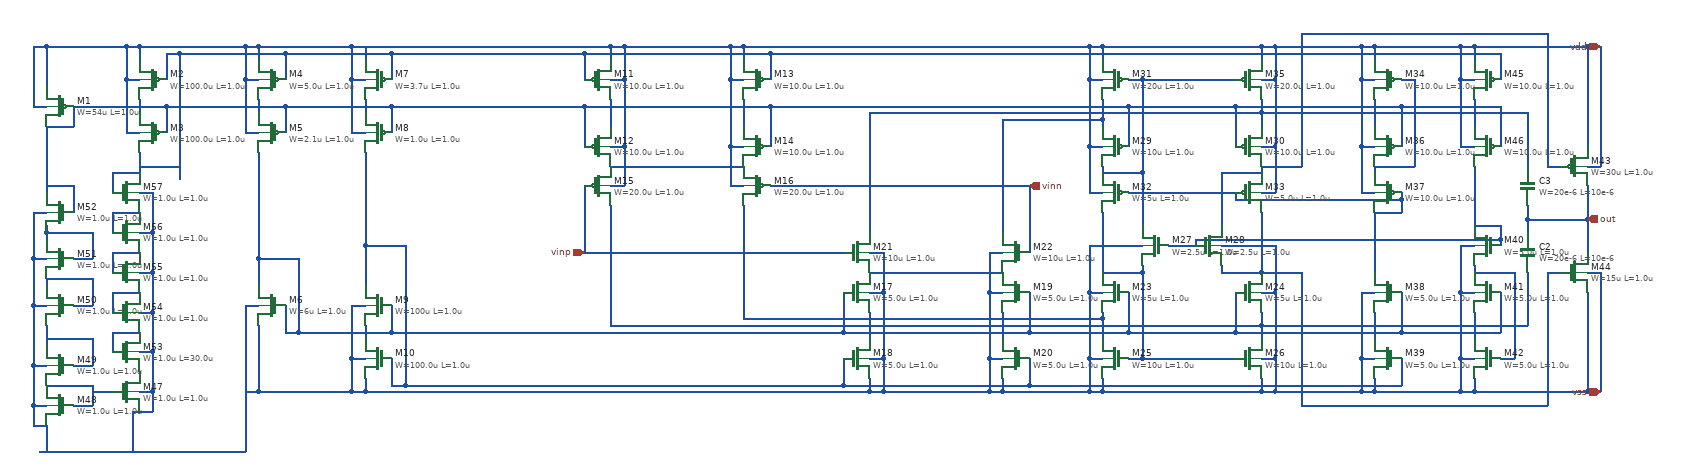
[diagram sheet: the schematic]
v {xschem version=3.4.8RC file_version=1.3}
G {}
K {}
V {}
S {}
F {}
E {}
N -450 -60 -430 -60 {
lab=vdd}
N -270 -60 -250 -60 {
lab=vdd}
N -450 -270 -450 -250 {
lab=vdd}
N -450 -220 -430 -220 {
lab=vdd}
N -490 -260 -490 -220 {
lab=#net1}
N 270 200 270 250 {
lab=vss}
N 270 200 290 200 {
lab=vss}
N 290 230 290 250 {
lab=vss}
N 290 -270 290 -250 {
lab=vdd}
N 270 -220 290 -220 {
lab=vdd}
N 530 -270 530 -250 {
lab=vdd}
N 530 -220 550 -220 {
lab=vdd}
N 550 -220 550 -120 {
lab=vdd}
N 530 200 550 200 {
lab=vss}
N 530 230 530 250 {
lab=vss}
N -490 -60 -490 40 {
lab=vinp}
N 120 40 140 40 {
lab=vss}
N -60 100 -40 100 {
lab=vss}
N -40 200 -40 250 {
lab=vss}
N -60 200 -40 200 {
lab=vss}
N -60 130 -60 170 {
lab=#net2}
N -60 230 -60 250 {
lab=vss}
N -100 200 -100 240 {
lab=#net3}
N -100 100 -100 160 {
lab=#net4}
N -450 -120 -430 -120 {
lab=vdd}
N -450 -190 -450 -150 {
lab=#net5}
N -490 -180 -490 -120 {
lab=#net6}
N 270 -220 270 -120 {
lab=vdd}
N 270 -120 290 -120 {
lab=vdd}
N 290 -160 290 -150 {
lab=#net7}
N 270 100 290 100 {
lab=vss}
N 270 100 270 200 {
lab=vss}
N 290 140 290 170 {
lab=#net8}
N 530 150 530 170 {
lab=#net9}
N 530 100 550 100 {
lab=vss}
N -210 -60 180 -60 {
lab=vinn}
N 180 -60 180 40 {
lab=vinn}
N 530 -120 550 -120 {
lab=vdd}
N 530 -170 530 -150 {
lab=#net10}
N -450 -90 -250 -90 {
lab=#net11}
N -490 40 -100 40 {
lab=vinp}
N -60 70 140 70 {
lab=#net12}
N 290 -90 290 -80 {
lab=#net13}
N 270 -50 290 -50 {
lab=vdd}
N 270 -120 270 -50 {
lab=vdd}
N 350 200 490 200 {
lab=#net14}
N 550 200 550 250 {
lab=vss}
N 390 30 430 30 {
lab=#net15}
N 530 -50 550 -50 {
lab=vdd}
N 550 -120 550 -50 {
lab=vdd}
N 530 -90 530 -80 {
lab=#net16}
N 470 30 550 30 {
lab=vss}
N 550 30 550 100 {
lab=vss}
N 1020 -10 1020 40 {
lab=out}
N 1020 -90 1040 -90 {
lab=vdd}
N 1040 -270 1040 -90 {
lab=vdd}
N 700 -270 830 -270 {
lab=vdd}
N 1020 70 1040 70 {
lab=vss}
N 1040 70 1040 250 {
lab=vss}
N 1020 100 1020 250 {
lab=vss}
N 1020 -270 1020 -120 {
lab=vdd}
N 680 -220 700 -220 {
lab=vdd}
N 680 -270 680 -220 {
lab=vdd}
N 700 -270 700 -250 {
lab=vdd}
N 700 -190 700 -150 {
lab=#net17}
N 680 -120 700 -120 {
lab=vdd}
N 680 -220 680 -120 {
lab=vdd}
N 700 -90 700 -80 {
lab=#net18}
N 680 -50 700 -50 {
lab=vdd}
N 680 -120 680 -50 {
lab=vdd}
N 680 100 700 100 {
lab=vss}
N 680 200 680 250 {
lab=vss}
N 680 200 700 200 {
lab=vss}
N 700 130 700 170 {
lab=#net19}
N 700 230 700 250 {
lab=vss}
N 740 200 740 240 {
lab=#net3}
N 740 100 740 160 {
lab=#net4}
N 830 -220 850 -220 {
lab=vdd}
N 830 -270 830 -220 {
lab=vdd}
N 850 -270 850 -250 {
lab=vdd}
N 850 -190 850 -150 {
lab=#net20}
N 830 -120 850 -120 {
lab=vdd}
N 830 -220 830 -120 {
lab=vdd}
N 830 100 850 100 {
lab=vss}
N 830 200 830 250 {
lab=vss}
N 830 200 850 200 {
lab=vss}
N 850 130 850 170 {
lab=#net21}
N 850 230 850 250 {
lab=vss}
N 850 60 850 70 {
lab=#net22}
N 830 30 850 30 {
lab=vss}
N 830 30 830 100 {
lab=vss}
N 850 -270 1020 -270 {
lab=vdd}
N -250 -270 -250 -250 {
lab=vdd}
N -270 -220 -250 -220 {
lab=vdd}
N -210 -260 -210 -220 {
lab=#net1}
N -270 -120 -250 -120 {
lab=vdd}
N -250 -190 -250 -150 {
lab=#net23}
N -210 -180 -210 -120 {
lab=#net6}
N 120 100 140 100 {
lab=vss}
N 120 200 140 200 {
lab=vss}
N 140 130 140 170 {
lab=#net24}
N 140 230 140 250 {
lab=vss}
N 180 200 180 240 {
lab=#net3}
N 180 100 180 160 {
lab=#net4}
N -60 40 -40 40 {
lab=vss}
N 740 -180 740 -120 {
lab=#net6}
N 740 -220 760 -220 {
lab=#net18}
N 760 -220 760 -90 {
lab=#net18}
N 700 -90 760 -90 {
lab=#net18}
N 740 -40 740 -20 {
lab=#net25}
N 700 -20 740 -20 {
lab=#net25}
N 700 -20 700 70 {
lab=#net25}
N 890 -260 890 -220 {
lab=#net1}
N 890 -180 890 -120 {
lab=#net6}
N 490 160 740 160 {
lab=#net4}
N 890 100 890 160 {
lab=#net4}
N 890 200 910 200 {
lab=#net22}
N 910 70 910 200 {
lab=#net22}
N 850 70 910 70 {
lab=#net22}
N 890 20 890 30 {
lab=#net15}
N 850 0 890 0 {
lab=#net15}
N 850 -90 850 0 {
lab=#net15}
N 350 -220 490 -220 {
lab=#net13}
N 330 -180 330 -120 {
lab=#net6}
N 490 -180 490 -120 {
lab=#net6}
N 330 -50 490 -50 {
lab=#net25}
N 290 -20 290 70 {
lab=#net14}
N 350 60 350 70 {
lab=#net14}
N 290 70 350 70 {
lab=#net14}
N 470 60 470 70 {
lab=#net26}
N 470 70 530 70 {
lab=#net26}
N 270 30 350 30 {
lab=vss}
N 270 30 270 100 {
lab=vss}
N 530 -20 530 70 {
lab=#net26}
N 350 -80 350 0 {
lab=#net13}
N 290 -80 350 -80 {
lab=#net13}
N 470 -80 470 0 {
lab=#net16}
N 470 -80 530 -80 {
lab=#net16}
N 740 -180 890 -180 {
lab=#net6}
N 180 240 740 240 {
lab=#net3}
N 740 160 890 160 {
lab=#net4}
N 490 -40 740 -40 {
lab=#net25}
N 490 -50 490 -40 {
lab=#net25}
N 430 20 890 20 {
lab=#net15}
N 430 20 430 30 {
lab=#net15}
N -450 -30 -450 150 {
lab=#net9}
N -250 -30 -250 140 {
lab=#net8}
N -60 -170 -60 10 {
lab=#net10}
N 140 -160 140 10 {
lab=#net7}
N 330 100 330 160 {
lab=#net4}
N 490 100 490 160 {
lab=#net4}
N 350 70 350 200 {
lab=#net14}
N 350 -220 350 -80 {
lab=#net13}
N 1020 -270 1040 -270 {
lab=vdd}
N 960 -90 980 -90 {
lab=#net16}
N 960 -290 960 -90 {
lab=#net16}
N 590 -290 960 -290 {
lab=#net16}
N 590 -290 590 -90 {
lab=#net16}
N 530 -90 590 -90 {
lab=#net16}
N 960 70 980 70 {
lab=#net26}
N 960 70 960 270 {
lab=#net26}
N 590 270 960 270 {
lab=#net26}
N 590 70 590 270 {
lab=#net26}
N 530 70 590 70 {
lab=#net26}
N 530 150 930 150 {
lab=#net9}
N 930 -10 930 10 {
lab=out}
N -60 -170 530 -170 {
lab=#net10}
N 140 -160 290 -160 {
lab=#net7}
N -250 140 290 140 {
lab=#net8}
N -450 150 530 150 {
lab=#net9}
N 270 -270 290 -270 {
lab=vdd}
N 530 -270 550 -270 {
lab=vdd}
N 1020 250 1040 250 {
lab=vss}
N -100 160 180 160 {
lab=#net4}
N -100 240 180 240 {
lab=#net3}
N -490 -260 -210 -260 {
lab=#net1}
N -490 -180 -210 -180 {
lab=#net6}
N 490 -180 740 -180 {
lab=#net6}
N -210 -260 890 -260 {
lab=#net1}
N -270 -270 -250 -270 {
lab=vdd}
N -640 -260 -490 -260 {
lab=#net1}
N -640 -180 -490 -180 {
lab=#net6}
N -640 160 -100 160 {
lab=#net4}
N -620 240 -100 240 {
lab=#net3}
N 930 -10 1020 -10 {
lab=out}
N 930 70 930 150 {
lab=#net9}
N 530 -170 930 -170 {
lab=#net10}
N 930 -170 930 -90 {
lab=#net10}
N 930 -30 930 -10 {
lab=out}
N -270 -220 -270 -120 {
lab=vdd}
N -430 -220 -430 -120 {
lab=vdd}
N 120 200 120 250 {
lab=vss}
N -40 40 -40 100 {
lab=vss}
N 120 40 120 100 {
lab=vss}
N -430 -120 -430 -60 {
lab=vdd}
N -270 -120 -270 -60 {
lab=vdd}
N -430 -270 -430 -220 {
lab=vdd}
N 140 250 270 250 {
lab=vss}
N 270 250 290 250 {
lab=vss}
N 270 -270 270 -220 {
lab=vdd}
N 290 -270 530 -270 {
lab=vdd}
N 550 -270 550 -220 {
lab=vdd}
N 550 100 550 200 {
lab=vss}
N 290 250 530 250 {
lab=vss}
N -60 250 -40 250 {
lab=vss}
N -40 100 -40 200 {
lab=vss}
N 530 250 550 250 {
lab=vss}
N 850 250 1020 250 {
lab=vss}
N 550 -270 680 -270 {
lab=vdd}
N 680 -270 700 -270 {
lab=vdd}
N 550 250 680 250 {
lab=vss}
N 680 100 680 200 {
lab=vss}
N 680 250 700 250 {
lab=vss}
N 830 -270 850 -270 {
lab=vdd}
N 700 250 830 250 {
lab=vss}
N 830 100 830 200 {
lab=vss}
N 830 250 850 250 {
lab=vss}
N -270 -270 -270 -220 {
lab=vdd}
N 120 100 120 200 {
lab=vss}
N 120 250 140 250 {
lab=vss}
N -210 -180 330 -180 {
lab=#net6}
N 330 -180 490 -180 {
lab=#net6}
N 740 -50 740 -40 {
lab=#net25}
N 890 0 890 20 {
lab=#net15}
N 180 160 330 160 {
lab=#net4}
N 330 160 490 160 {
lab=#net4}
N 330 200 350 200 {
lab=#net14}
N 330 -220 350 -220 {
lab=#net13}
N 530 130 530 150 {
lab=#net9}
N 530 -190 530 -170 {
lab=#net10}
N 290 -190 290 -160 {
lab=#net7}
N 290 130 290 140 {
lab=#net8}
N 1020 -60 1020 -10 {
lab=out}
N -40 250 120 250 {
lab=vss}
N -450 -270 -430 -270 {
lab=vdd}
N -250 -270 270 -270 {
lab=vdd}
N -430 -270 -270 -270 {
lab=vdd}
N -740 -260 -590 -260 {
lab=#net1}
N -740 -180 -590 -180 {
lab=#net6}
N -740 160 -600 160 {lab=#net4}
N -720 240 -600 240 {lab=#net3}
N -800 250 -60 250 {lab=vss}
N -780 -270 -450 -270 {lab=vdd}
N -840 120 -820 120 {
lab=vss}
N -840 200 -840 250 {
lab=vss}
N -840 200 -820 200 {
lab=vss}
N -820 150 -820 170 {
lab=#net27}
N -820 230 -820 250 {
lab=vss}
N -820 -270 -820 -250 {
lab=vdd}
N -840 -220 -820 -220 {
lab=vdd}
N -840 -140 -820 -140 {
lab=vdd}
N -840 -220 -840 -140 {
lab=vdd}
N -820 -190 -820 -170 {
lab=#net28}
N -780 -180 -780 -140 {
lab=#net6}
N -780 -260 -780 -220 {
lab=#net1}
N -980 -270 -980 -250 {
lab=vdd}
N -1000 -220 -980 -220 {
lab=vdd}
N -1000 -140 -980 -140 {
lab=vdd}
N -1000 -220 -1000 -140 {
lab=vdd}
N -980 -190 -980 -170 {
lab=#net29}
N -940 -180 -940 -140 {
lab=#net6}
N -940 -260 -940 -220 {
lab=#net1}
N -1000 120 -980 120 {
lab=vss}
N -1000 120 -1000 250 {
lab=vss}
N -980 150 -980 250 {
lab=vss}
N -940 120 -940 160 {
lab=#net4}
N -940 160 -920 160 {
lab=#net4}
N -980 50 -920 50 {
lab=#net4}
N -780 120 -780 160 {
lab=#net4}
N -780 200 -780 240 {
lab=#net3}
N -780 240 -760 240 {
lab=#net3}
N -920 160 -780 160 {
lab=#net4}
N -820 30 -760 30 {
lab=#net3}
N -980 -110 -980 50 {
lab=#net4}
N -820 -110 -820 30 {
lab=#net3}
N -920 50 -920 160 {
lab=#net4}
N -760 30 -760 240 {
lab=#net3}
N -820 30 -820 90 {
lab=#net3}
N -980 50 -980 90 {
lab=#net4}
N -780 -260 -630 -260 {
lab=#net1}
N -780 -180 -630 -180 {
lab=#net6}
N -1170 340 -1010 340 {
lab=vss}
N -1160 -270 -1160 -250 {
lab=vdd}
N -1180 -220 -1160 -220 {
lab=vdd}
N -1180 -140 -1160 -140 {
lab=vdd}
N -1180 -220 -1180 -140 {
lab=vdd}
N -1160 -190 -1160 -170 {
lab=#net30}
N -1120 -180 -1120 -140 {
lab=#net6}
N -1120 -260 -1120 -220 {
lab=#net1}
N -1300 -270 -1300 -190 {
lab=vdd}
N -1320 -270 -1320 -180 {
lab=vdd}
N -1240 -180 -1120 -180 {
lab=#net6}
N -1300 -70 -1300 -50 {
lab=#net6}
N -1160 -110 -1160 -70 {
lab=#net1}
N -1100 -260 -1100 -70 {
lab=#net1}
N -1230 250 -1200 250 {
lab=#net31}
N -1320 270 -1300 270 {
lab=vss}
N -1320 270 -1320 300 {
lab=vss}
N -1320 300 -1300 300 {
lab=vss}
N -1160 250 -1140 250 {
lab=vss}
N -1140 250 -1140 280 {
lab=vss}
N -1160 280 -1140 280 {
lab=vss}
N -1320 210 -1300 210 {
lab=vss}
N -1320 210 -1320 270 {
lab=vss}
N -1230 190 -1230 210 {
lab=#net32}
N -980 250 -840 250 {
lab=vss}
N -840 120 -840 200 {
lab=vss}
N -840 250 -820 250 {
lab=vss}
N -840 -270 -820 -270 {
lab=vdd}
N -840 -270 -840 -220 {
lab=vdd}
N -940 -180 -780 -180 {
lab=#net6}
N -940 -260 -780 -260 {
lab=#net1}
N -1000 -270 -980 -270 {
lab=vdd}
N -1000 -270 -1000 -220 {
lab=vdd}
N -1120 -180 -940 -180 {
lab=#net6}
N -1100 -260 -940 -260 {
lab=#net1}
N -1000 250 -980 250 {
lab=vss}
N -1180 -270 -1160 -270 {
lab=vdd}
N -1180 -270 -1180 -220 {
lab=vdd}
N -1320 -270 -1300 -270 {
lab=vdd}
N -1260 -180 -1240 -180 {
lab=#net6}
N -1120 -260 -1100 -260 {
lab=#net1}
N -1300 340 -1160 340 {
lab=vss}
N -1260 210 -1230 210 {
lab=#net32}
N -1260 270 -1230 270 {
lab=#net31}
N -980 -270 -840 -270 {
lab=vdd}
N -1160 -270 -1000 -270 {
lab=vdd}
N -1300 -270 -1180 -270 {
lab=vdd}
N -780 160 -640 160 {lab=#net4}
N -760 240 -640 240 {lab=#net3}
N -1300 150 -1300 180 {lab=#net32}
N -1260 120 -1230 120 {lab=#net33}
N -1320 120 -1300 120 {lab=vss}
N -1320 120 -1320 210 {lab=vss}
N -1230 80 -1230 120 {lab=#net33}
N -1300 80 -1230 80 {lab=#net33}
N -1230 170 -1230 190 {lab=#net32}
N -1300 170 -1230 170 {lab=#net32}
N -1000 240 -1000 340 {lab=vss}
N -1030 340 -1000 340 {lab=vss}
N -1170 280 -1170 340 {lab=vss}
N -1170 280 -1160 280 {lab=vss}
N -1260 50 -1230 50 {lab=#net34}
N -1230 10 -1230 50 {lab=#net34}
N -1310 340 -1280 340 {lab=vss}
N -1300 80 -1300 90 {lab=#net33}
N -1300 0 -1300 10 {lab=#net34}
N -1300 10 -1280 10 {lab=#net34}
N -1300 10 -1300 20 {lab=#net34}
N -1320 50 -1320 120 {lab=vss}
N -1320 50 -1300 50 {lab=vss}
N -1300 240 -1230 240 {lab=#net31}
N -1230 240 -1230 270 {lab=#net31}
N -1320 -20 -1300 -20 {lab=vss}
N -1320 -20 -1320 50 {lab=vss}
N -1260 -60 -1260 -20 {lab=#net6}
N -1300 -60 -1260 -60 {lab=#net6}
N -1320 -180 -1300 -180 {lab=vdd}
N -1260 -180 -1260 -150 {lab=#net6}
N -1300 -150 -1260 -150 {lab=#net6}
N -1300 -150 -1300 -90 {lab=#net6}
N -1280 10 -1230 10 {lab=#net34}
N -1300 300 -1300 340 {lab=vss}
N -1300 -90 -1300 -70 {lab=#net6}
N -1200 160 -1200 190 {lab=#net35}
N -1200 160 -1160 160 {lab=#net35}
N -1160 190 -1140 190 {lab=vss}
N -1140 190 -1140 250 {lab=vss}
N -1160 190 -1140 190 {
lab=vss}
N -1200 100 -1200 130 {lab=#net36}
N -1200 100 -1160 100 {lab=#net36}
N -1160 130 -1140 130 {lab=vss}
N -1140 130 -1140 190 {lab=vss}
N -1200 40 -1200 70 {lab=#net37}
N -1200 40 -1160 40 {lab=#net37}
N -1160 70 -1140 70 {lab=vss}
N -1140 70 -1140 130 {lab=vss}
N -1200 -20 -1200 10 {lab=#net38}
N -1200 -20 -1160 -20 {lab=#net38}
N -1160 10 -1140 10 {lab=vss}
N -1140 10 -1140 70 {lab=vss}
N -1200 -80 -1200 -50 {lab=#net1}
N -1200 -80 -1160 -80 {lab=#net1}
N -1160 -50 -1140 -50 {lab=vss}
N -1140 -50 -1140 10 {lab=vss}
N -1160 -90 -1100 -90 {lab=#net1}
N -830 -270 -780 -270 {lab=vdd}
N -820 250 -790 250 {lab=vss}
C {devices/opin.sym} 1020 -10 0 0 {name=p1 lab=out}
C {devices/iopin.sym} 1040 -270 0 0 {name=p3 lab=vdd}
C {devices/iopin.sym} 1040 250 0 0 {name=p4 lab=vss}
C {devices/ipin.sym} -490 40 0 0 {name=p2 lab=vinp}
C {devices/ipin.sym} 180 -60 0 1 {name=p5 lab=vinn}
C {symbols/pfet_06v0.sym} -470 -220 0 0 {name=M11
L=1.0u
W=10.0u
nf=1
m=1
ad="'int((nf+1)/2) * W/nf * 0.18u'"
pd="'2*int((nf+1)/2) * (W/nf + 0.18u)'"
as="'int((nf+2)/2) * W/nf * 0.18u'"
ps="'2*int((nf+2)/2) * (W/nf + 0.18u)'"
nrd="'0.18u / W'" nrs="'0.18u / W'"
sa=0 sb=0 sd=0
model=pfet_06v0
spiceprefix=X
}
C {symbols/pfet_06v0.sym} -470 -120 0 0 {name=M12
L=1.0u
W=10.0u
nf=1
m=1
ad="'int((nf+1)/2) * W/nf * 0.18u'"
pd="'2*int((nf+1)/2) * (W/nf + 0.18u)'"
as="'int((nf+2)/2) * W/nf * 0.18u'"
ps="'2*int((nf+2)/2) * (W/nf + 0.18u)'"
nrd="'0.18u / W'" nrs="'0.18u / W'"
sa=0 sb=0 sd=0
model=pfet_06v0
spiceprefix=X
}
C {symbols/pfet_06v0.sym} -230 -220 0 1 {name=M13
L=1.0u
W=10.0u
nf=1
m=1
ad="'int((nf+1)/2) * W/nf * 0.18u'"
pd="'2*int((nf+1)/2) * (W/nf + 0.18u)'"
as="'int((nf+2)/2) * W/nf * 0.18u'"
ps="'2*int((nf+2)/2) * (W/nf + 0.18u)'"
nrd="'0.18u / W'" nrs="'0.18u / W'"
sa=0 sb=0 sd=0
model=pfet_06v0
spiceprefix=X
}
C {symbols/pfet_06v0.sym} -230 -120 0 1 {name=M14
L=1.0u
W=10.0u
nf=1
m=1
ad="'int((nf+1)/2) * W/nf * 0.18u'"
pd="'2*int((nf+1)/2) * (W/nf + 0.18u)'"
as="'int((nf+2)/2) * W/nf * 0.18u'"
ps="'2*int((nf+2)/2) * (W/nf + 0.18u)'"
nrd="'0.18u / W'" nrs="'0.18u / W'"
sa=0 sb=0 sd=0
model=pfet_06v0
spiceprefix=X
}
C {symbols/pfet_06v0.sym} -470 -60 0 0 {name=M15
L=1.0u
W=20.0u
nf=2
m=1
ad="'int((nf+1)/2) * W/nf * 0.18u'"
pd="'2*int((nf+1)/2) * (W/nf + 0.18u)'"
as="'int((nf+2)/2) * W/nf * 0.18u'"
ps="'2*int((nf+2)/2) * (W/nf + 0.18u)'"
nrd="'0.18u / W'" nrs="'0.18u / W'"
sa=0 sb=0 sd=0
model=pfet_06v0
spiceprefix=X
}
C {symbols/pfet_06v0.sym} -230 -60 0 1 {name=M16
L=1.0u
W=20.0u
nf=2
m=1
ad="'int((nf+1)/2) * W/nf * 0.18u'"
pd="'2*int((nf+1)/2) * (W/nf + 0.18u)'"
as="'int((nf+2)/2) * W/nf * 0.18u'"
ps="'2*int((nf+2)/2) * (W/nf + 0.18u)'"
nrd="'0.18u / W'" nrs="'0.18u / W'"
sa=0 sb=0 sd=0
model=pfet_06v0
spiceprefix=X
}
C {symbols/nfet_06v0.sym} -80 100 0 0 {name=M17
L=1.0u
W=5.0u
nf=1
m=1
ad="'int((nf+1)/2) * W/nf * 0.18u'"
pd="'2*int((nf+1)/2) * (W/nf + 0.18u)'"
as="'int((nf+2)/2) * W/nf * 0.18u'"
ps="'2*int((nf+2)/2) * (W/nf + 0.18u)'"
nrd="'0.18u / W'" nrs="'0.18u / W'"
sa=0 sb=0 sd=0
model=nfet_06v0
spiceprefix=X
}
C {symbols/nfet_06v0.sym} -80 200 0 0 {name=M18
L=1.0u
W=5.0u
nf=1
m=1
ad="'int((nf+1)/2) * W/nf * 0.18u'"
pd="'2*int((nf+1)/2) * (W/nf + 0.18u)'"
as="'int((nf+2)/2) * W/nf * 0.18u'"
ps="'2*int((nf+2)/2) * (W/nf + 0.18u)'"
nrd="'0.18u / W'" nrs="'0.18u / W'"
sa=0 sb=0 sd=0
model=nfet_06v0
spiceprefix=X
}
C {symbols/nfet_06v0.sym} 160 100 0 1 {name=M19
L=1.0u
W=5.0u
nf=1
m=1
ad="'int((nf+1)/2) * W/nf * 0.18u'"
pd="'2*int((nf+1)/2) * (W/nf + 0.18u)'"
as="'int((nf+2)/2) * W/nf * 0.18u'"
ps="'2*int((nf+2)/2) * (W/nf + 0.18u)'"
nrd="'0.18u / W'" nrs="'0.18u / W'"
sa=0 sb=0 sd=0
model=nfet_06v0
spiceprefix=X
}
C {symbols/nfet_06v0.sym} 160 200 0 1 {name=M20
L=1.0u
W=5.0u
nf=1
m=1
ad="'int((nf+1)/2) * W/nf * 0.18u'"
pd="'2*int((nf+1)/2) * (W/nf + 0.18u)'"
as="'int((nf+2)/2) * W/nf * 0.18u'"
ps="'2*int((nf+2)/2) * (W/nf + 0.18u)'"
nrd="'0.18u / W'" nrs="'0.18u / W'"
sa=0 sb=0 sd=0
model=nfet_06v0
spiceprefix=X
}
C {symbols/nfet_06v0.sym} -80 40 0 0 {name=M21
L=1.0u
W=10u
nf=2
m=1
ad="'int((nf+1)/2) * W/nf * 0.18u'"
pd="'2*int((nf+1)/2) * (W/nf + 0.18u)'"
as="'int((nf+2)/2) * W/nf * 0.18u'"
ps="'2*int((nf+2)/2) * (W/nf + 0.18u)'"
nrd="'0.18u / W'" nrs="'0.18u / W'"
sa=0 sb=0 sd=0
model=nfet_06v0
spiceprefix=X
}
C {symbols/nfet_06v0.sym} 160 40 0 1 {name=M22
L=1.0u
W=10u
nf=2
m=1
ad="'int((nf+1)/2) * W/nf * 0.18u'"
pd="'2*int((nf+1)/2) * (W/nf + 0.18u)'"
as="'int((nf+2)/2) * W/nf * 0.18u'"
ps="'2*int((nf+2)/2) * (W/nf + 0.18u)'"
nrd="'0.18u / W'" nrs="'0.18u / W'"
sa=0 sb=0 sd=0
model=nfet_06v0
spiceprefix=X
}
C {symbols/pfet_06v0.sym} 310 -120 0 1 {name=M29
L=1.0u
W=10u
nf=2
m=1
ad="'int((nf+1)/2) * W/nf * 0.18u'"
pd="'2*int((nf+1)/2) * (W/nf + 0.18u)'"
as="'int((nf+2)/2) * W/nf * 0.18u'"
ps="'2*int((nf+2)/2) * (W/nf + 0.18u)'"
nrd="'0.18u / W'" nrs="'0.18u / W'"
sa=0 sb=0 sd=0
model=pfet_06v0
spiceprefix=X
}
C {symbols/pfet_06v0.sym} 510 -120 0 0 {name=M30
L=1.0u
W=10.0u
nf=2
m=1
ad="'int((nf+1)/2) * W/nf * 0.18u'"
pd="'2*int((nf+1)/2) * (W/nf + 0.18u)'"
as="'int((nf+2)/2) * W/nf * 0.18u'"
ps="'2*int((nf+2)/2) * (W/nf + 0.18u)'"
nrd="'0.18u / W'" nrs="'0.18u / W'"
sa=0 sb=0 sd=0
model=pfet_06v0
spiceprefix=X
}
C {symbols/pfet_06v0.sym} 310 -220 0 1 {name=M31
L=1.0u
W=20u
nf=4
m=1
ad="'int((nf+1)/2) * W/nf * 0.18u'"
pd="'2*int((nf+1)/2) * (W/nf + 0.18u)'"
as="'int((nf+2)/2) * W/nf * 0.18u'"
ps="'2*int((nf+2)/2) * (W/nf + 0.18u)'"
nrd="'0.18u / W'" nrs="'0.18u / W'"
sa=0 sb=0 sd=0
model=pfet_06v0
spiceprefix=X
}
C {symbols/pfet_06v0.sym} 510 -220 0 0 {name=M35
L=1.0u
W=20.0u
nf=4
m=1
ad="'int((nf+1)/2) * W/nf * 0.18u'"
pd="'2*int((nf+1)/2) * (W/nf + 0.18u)'"
as="'int((nf+2)/2) * W/nf * 0.18u'"
ps="'2*int((nf+2)/2) * (W/nf + 0.18u)'"
nrd="'0.18u / W'" nrs="'0.18u / W'"
sa=0 sb=0 sd=0
model=pfet_06v0
spiceprefix=X
}
C {symbols/pfet_06v0.sym} 310 -50 0 1 {name=M32
L=1.0u
W=5u
nf=1
m=1
ad="'int((nf+1)/2) * W/nf * 0.18u'"
pd="'2*int((nf+1)/2) * (W/nf + 0.18u)'"
as="'int((nf+2)/2) * W/nf * 0.18u'"
ps="'2*int((nf+2)/2) * (W/nf + 0.18u)'"
nrd="'0.18u / W'" nrs="'0.18u / W'"
sa=0 sb=0 sd=0
model=pfet_06v0
spiceprefix=X
}
C {symbols/pfet_06v0.sym} 510 -50 0 0 {name=M33
L=1.0u
W=5.0u
nf=1
m=1
ad="'int((nf+1)/2) * W/nf * 0.18u'"
pd="'2*int((nf+1)/2) * (W/nf + 0.18u)'"
as="'int((nf+2)/2) * W/nf * 0.18u'"
ps="'2*int((nf+2)/2) * (W/nf + 0.18u)'"
nrd="'0.18u / W'" nrs="'0.18u / W'"
sa=0 sb=0 sd=0
model=pfet_06v0
spiceprefix=X
}
C {symbols/nfet_06v0.sym} 310 100 0 1 {name=M23
L=1.0u
W=5u
nf=2
m=1
ad="'int((nf+1)/2) * W/nf * 0.18u'"
pd="'2*int((nf+1)/2) * (W/nf + 0.18u)'"
as="'int((nf+2)/2) * W/nf * 0.18u'"
ps="'2*int((nf+2)/2) * (W/nf + 0.18u)'"
nrd="'0.18u / W'" nrs="'0.18u / W'"
sa=0 sb=0 sd=0
model=nfet_06v0
spiceprefix=X
}
C {symbols/nfet_06v0.sym} 510 100 0 0 {name=M24
L=1.0u
W=5u
nf=2
m=1
ad="'int((nf+1)/2) * W/nf * 0.18u'"
pd="'2*int((nf+1)/2) * (W/nf + 0.18u)'"
as="'int((nf+2)/2) * W/nf * 0.18u'"
ps="'2*int((nf+2)/2) * (W/nf + 0.18u)'"
nrd="'0.18u / W'" nrs="'0.18u / W'"
sa=0 sb=0 sd=0
model=nfet_06v0
spiceprefix=X
}
C {symbols/nfet_06v0.sym} 310 200 0 1 {name=M25
L=1.0u
W=10u
nf=4
m=1
ad="'int((nf+1)/2) * W/nf * 0.18u'"
pd="'2*int((nf+1)/2) * (W/nf + 0.18u)'"
as="'int((nf+2)/2) * W/nf * 0.18u'"
ps="'2*int((nf+2)/2) * (W/nf + 0.18u)'"
nrd="'0.18u / W'" nrs="'0.18u / W'"
sa=0 sb=0 sd=0
model=nfet_06v0
spiceprefix=X
}
C {symbols/nfet_06v0.sym} 510 200 0 0 {name=M26
L=1.0u
W=10u
nf=4
m=1
ad="'int((nf+1)/2) * W/nf * 0.18u'"
pd="'2*int((nf+1)/2) * (W/nf + 0.18u)'"
as="'int((nf+2)/2) * W/nf * 0.18u'"
ps="'2*int((nf+2)/2) * (W/nf + 0.18u)'"
nrd="'0.18u / W'" nrs="'0.18u / W'"
sa=0 sb=0 sd=0
model=nfet_06v0
spiceprefix=X
}
C {symbols/nfet_06v0.sym} 370 30 0 1 {name=M27
L=1.0u
W=2.5u
nf=1
m=1
ad="'int((nf+1)/2) * W/nf * 0.18u'"
pd="'2*int((nf+1)/2) * (W/nf + 0.18u)'"
as="'int((nf+2)/2) * W/nf * 0.18u'"
ps="'2*int((nf+2)/2) * (W/nf + 0.18u)'"
nrd="'0.18u / W'" nrs="'0.18u / W'"
sa=0 sb=0 sd=0
model=nfet_06v0
spiceprefix=X
}
C {symbols/nfet_06v0.sym} 450 30 0 0 {name=M28
L=1.0u
W=2.5u
nf=1
m=1
ad="'int((nf+1)/2) * W/nf * 0.18u'"
pd="'2*int((nf+1)/2) * (W/nf + 0.18u)'"
as="'int((nf+2)/2) * W/nf * 0.18u'"
ps="'2*int((nf+2)/2) * (W/nf + 0.18u)'"
nrd="'0.18u / W'" nrs="'0.18u / W'"
sa=0 sb=0 sd=0
model=nfet_06v0
spiceprefix=X
}
C {symbols/pfet_06v0.sym} 720 -220 0 1 {name=M34
L=1.0u
W=10.0u
nf=1
m=1
ad="'int((nf+1)/2) * W/nf * 0.18u'"
pd="'2*int((nf+1)/2) * (W/nf + 0.18u)'"
as="'int((nf+2)/2) * W/nf * 0.18u'"
ps="'2*int((nf+2)/2) * (W/nf + 0.18u)'"
nrd="'0.18u / W'" nrs="'0.18u / W'"
sa=0 sb=0 sd=0
model=pfet_06v0
spiceprefix=X
}
C {symbols/pfet_06v0.sym} 720 -120 0 1 {name=M36
L=1.0u
W=10.0u
nf=1
m=1
ad="'int((nf+1)/2) * W/nf * 0.18u'"
pd="'2*int((nf+1)/2) * (W/nf + 0.18u)'"
as="'int((nf+2)/2) * W/nf * 0.18u'"
ps="'2*int((nf+2)/2) * (W/nf + 0.18u)'"
nrd="'0.18u / W'" nrs="'0.18u / W'"
sa=0 sb=0 sd=0
model=pfet_06v0
spiceprefix=X
}
C {symbols/pfet_06v0.sym} 720 -50 0 1 {name=M37
L=1.0u
W=10.0u
nf=1
m=1
ad="'int((nf+1)/2) * W/nf * 0.18u'"
pd="'2*int((nf+1)/2) * (W/nf + 0.18u)'"
as="'int((nf+2)/2) * W/nf * 0.18u'"
ps="'2*int((nf+2)/2) * (W/nf + 0.18u)'"
nrd="'0.18u / W'" nrs="'0.18u / W'"
sa=0 sb=0 sd=0
model=pfet_06v0
spiceprefix=X
}
C {symbols/nfet_06v0.sym} 720 100 0 1 {name=M38
L=1.0u
W=5.0u
nf=1
m=1
ad="'int((nf+1)/2) * W/nf * 0.18u'"
pd="'2*int((nf+1)/2) * (W/nf + 0.18u)'"
as="'int((nf+2)/2) * W/nf * 0.18u'"
ps="'2*int((nf+2)/2) * (W/nf + 0.18u)'"
nrd="'0.18u / W'" nrs="'0.18u / W'"
sa=0 sb=0 sd=0
model=nfet_06v0
spiceprefix=X
}
C {symbols/nfet_06v0.sym} 720 200 0 1 {name=M39
L=1.0u
W=5.0u
nf=1
m=1
ad="'int((nf+1)/2) * W/nf * 0.18u'"
pd="'2*int((nf+1)/2) * (W/nf + 0.18u)'"
as="'int((nf+2)/2) * W/nf * 0.18u'"
ps="'2*int((nf+2)/2) * (W/nf + 0.18u)'"
nrd="'0.18u / W'" nrs="'0.18u / W'"
sa=0 sb=0 sd=0
model=nfet_06v0
spiceprefix=X
}
C {symbols/pfet_06v0.sym} 870 -220 0 1 {name=M45
L=1.0u
W=10.0u
nf=1
m=1
ad="'int((nf+1)/2) * W/nf * 0.18u'"
pd="'2*int((nf+1)/2) * (W/nf + 0.18u)'"
as="'int((nf+2)/2) * W/nf * 0.18u'"
ps="'2*int((nf+2)/2) * (W/nf + 0.18u)'"
nrd="'0.18u / W'" nrs="'0.18u / W'"
sa=0 sb=0 sd=0
model=pfet_06v0
spiceprefix=X
}
C {symbols/pfet_06v0.sym} 870 -120 0 1 {name=M46
L=1.0u
W=10.0u
nf=1
m=1
ad="'int((nf+1)/2) * W/nf * 0.18u'"
pd="'2*int((nf+1)/2) * (W/nf + 0.18u)'"
as="'int((nf+2)/2) * W/nf * 0.18u'"
ps="'2*int((nf+2)/2) * (W/nf + 0.18u)'"
nrd="'0.18u / W'" nrs="'0.18u / W'"
sa=0 sb=0 sd=0
model=pfet_06v0
spiceprefix=X
}
C {symbols/nfet_06v0.sym} 870 30 0 1 {name=M40
L=1.0u
W=5.0u
nf=1
m=1
ad="'int((nf+1)/2) * W/nf * 0.18u'"
pd="'2*int((nf+1)/2) * (W/nf + 0.18u)'"
as="'int((nf+2)/2) * W/nf * 0.18u'"
ps="'2*int((nf+2)/2) * (W/nf + 0.18u)'"
nrd="'0.18u / W'" nrs="'0.18u / W'"
sa=0 sb=0 sd=0
model=nfet_06v0
spiceprefix=X
}
C {symbols/nfet_06v0.sym} 870 100 0 1 {name=M41
L=1.0u
W=5.0u
nf=1
m=1
ad="'int((nf+1)/2) * W/nf * 0.18u'"
pd="'2*int((nf+1)/2) * (W/nf + 0.18u)'"
as="'int((nf+2)/2) * W/nf * 0.18u'"
ps="'2*int((nf+2)/2) * (W/nf + 0.18u)'"
nrd="'0.18u / W'" nrs="'0.18u / W'"
sa=0 sb=0 sd=0
model=nfet_06v0
spiceprefix=X
}
C {symbols/nfet_06v0.sym} 870 200 0 1 {name=M42
L=1.0u
W=5.0u
nf=1
m=1
ad="'int((nf+1)/2) * W/nf * 0.18u'"
pd="'2*int((nf+1)/2) * (W/nf + 0.18u)'"
as="'int((nf+2)/2) * W/nf * 0.18u'"
ps="'2*int((nf+2)/2) * (W/nf + 0.18u)'"
nrd="'0.18u / W'" nrs="'0.18u / W'"
sa=0 sb=0 sd=0
model=nfet_06v0
spiceprefix=X
}
C {symbols/pfet_06v0.sym} 1000 -90 0 0 {name=M43
L=1.0u
W=30u
nf=3
m=1
ad="'int((nf+1)/2) * W/nf * 0.18u'"
pd="'2*int((nf+1)/2) * (W/nf + 0.18u)'"
as="'int((nf+2)/2) * W/nf * 0.18u'"
ps="'2*int((nf+2)/2) * (W/nf + 0.18u)'"
nrd="'0.18u / W'" nrs="'0.18u / W'"
sa=0 sb=0 sd=0
model=pfet_06v0
spiceprefix=X
}
C {symbols/nfet_06v0.sym} 1000 70 0 0 {name=M44
L=1.0u
W=15u
nf=3
m=1
ad="'int((nf+1)/2) * W/nf * 0.18u'"
pd="'2*int((nf+1)/2) * (W/nf + 0.18u)'"
as="'int((nf+2)/2) * W/nf * 0.18u'"
ps="'2*int((nf+2)/2) * (W/nf + 0.18u)'"
nrd="'0.18u / W'" nrs="'0.18u / W'"
sa=0 sb=0 sd=0
model=nfet_06v0
spiceprefix=X
}
C {symbols/cap_mim_2f0fF.sym} 930 40 0 0 {name=C2
W=20e-6
L=10e-6
model=cap_mim_2f0fF
spiceprefix=X
m=1}
C {symbols/cap_mim_2f0fF.sym} 930 -60 0 0 {name=C3
W=20e-6
L=10e-6
model=cap_mim_2f0fF
spiceprefix=X
m=1}
C {symbols/pfet_06v0.sym} -960 -220 0 1 {name=M4
L=1.0u
W=5.0u
nf=1
m=1
ad="'int((nf+1)/2) * W/nf * 0.18u'"
pd="'2*int((nf+1)/2) * (W/nf + 0.18u)'"
as="'int((nf+2)/2) * W/nf * 0.18u'"
ps="'2*int((nf+2)/2) * (W/nf + 0.18u)'"
nrd="'0.18u / W'" nrs="'0.18u / W'"
sa=0 sb=0 sd=0
model=pfet_06v0
spiceprefix=X
}
C {symbols/pfet_06v0.sym} -960 -140 0 1 {name=M5
L=1.0u
W=2.1u
nf=1
m=1
ad="'int((nf+1)/2) * W/nf * 0.18u'"
pd="'2*int((nf+1)/2) * (W/nf + 0.18u)'"
as="'int((nf+2)/2) * W/nf * 0.18u'"
ps="'2*int((nf+2)/2) * (W/nf + 0.18u)'"
nrd="'0.18u / W'" nrs="'0.18u / W'"
sa=0 sb=0 sd=0
model=pfet_06v0
spiceprefix=X
}
C {symbols/nfet_06v0.sym} -960 120 0 1 {name=M6
L=1.0u
W=6u
nf=1
m=1
ad="'int((nf+1)/2) * W/nf * 0.18u'"
pd="'2*int((nf+1)/2) * (W/nf + 0.18u)'"
as="'int((nf+2)/2) * W/nf * 0.18u'"
ps="'2*int((nf+2)/2) * (W/nf + 0.18u)'"
nrd="'0.18u / W'" nrs="'0.18u / W'"
sa=0 sb=0 sd=0
model=nfet_06v0
spiceprefix=X
}
C {symbols/pfet_06v0.sym} -800 -220 0 1 {name=M7
L=1.0u
W=3.7u
nf=1
m=1
ad="'int((nf+1)/2) * W/nf * 0.18u'"
pd="'2*int((nf+1)/2) * (W/nf + 0.18u)'"
as="'int((nf+2)/2) * W/nf * 0.18u'"
ps="'2*int((nf+2)/2) * (W/nf + 0.18u)'"
nrd="'0.18u / W'" nrs="'0.18u / W'"
sa=0 sb=0 sd=0
model=pfet_06v0
spiceprefix=X
}
C {symbols/pfet_06v0.sym} -800 -140 0 1 {name=M8
L=1.0u
W=1.0u
nf=10
m=1
ad="'int((nf+1)/2) * W/nf * 0.18u'"
pd="'2*int((nf+1)/2) * (W/nf + 0.18u)'"
as="'int((nf+2)/2) * W/nf * 0.18u'"
ps="'2*int((nf+2)/2) * (W/nf + 0.18u)'"
nrd="'0.18u / W'" nrs="'0.18u / W'"
sa=0 sb=0 sd=0
model=pfet_06v0
spiceprefix=X
}
C {symbols/nfet_06v0.sym} -800 120 0 1 {name=M9
L=1.0u
W=100u
nf=1
m=1
ad="'int((nf+1)/2) * W/nf * 0.18u'"
pd="'2*int((nf+1)/2) * (W/nf + 0.18u)'"
as="'int((nf+2)/2) * W/nf * 0.18u'"
ps="'2*int((nf+2)/2) * (W/nf + 0.18u)'"
nrd="'0.18u / W'" nrs="'0.18u / W'"
sa=0 sb=0 sd=0
model=nfet_06v0
spiceprefix=X
}
C {symbols/nfet_06v0.sym} -800 200 0 1 {name=M10
L=1.0u
W=100.0u
nf=1
m=1
ad="'int((nf+1)/2) * W/nf * 0.18u'"
pd="'2*int((nf+1)/2) * (W/nf + 0.18u)'"
as="'int((nf+2)/2) * W/nf * 0.18u'"
ps="'2*int((nf+2)/2) * (W/nf + 0.18u)'"
nrd="'0.18u / W'" nrs="'0.18u / W'"
sa=0 sb=0 sd=0
model=nfet_06v0
spiceprefix=X
}
C {symbols/pfet_06v0.sym} -1280 -180 0 1 {name=M1
L=1.0u
W=54u
nf=1
m=1
ad="'int((nf+1)/2) * W/nf * 0.18u'"
pd="'2*int((nf+1)/2) * (W/nf + 0.18u)'"
as="'int((nf+2)/2) * W/nf * 0.18u'"
ps="'2*int((nf+2)/2) * (W/nf + 0.18u)'"
nrd="'0.18u / W'" nrs="'0.18u / W'"
sa=0 sb=0 sd=0
model=pfet_06v0
spiceprefix=X
}
C {symbols/pfet_06v0.sym} -1140 -220 0 1 {name=M2
L=1.0u
W=100.0u
nf=1
m=1
ad="'int((nf+1)/2) * W/nf * 0.18u'"
pd="'2*int((nf+1)/2) * (W/nf + 0.18u)'"
as="'int((nf+2)/2) * W/nf * 0.18u'"
ps="'2*int((nf+2)/2) * (W/nf + 0.18u)'"
nrd="'0.18u / W'" nrs="'0.18u / W'"
sa=0 sb=0 sd=0
model=pfet_06v0
spiceprefix=X
}
C {symbols/pfet_06v0.sym} -1140 -140 0 1 {name=M3
L=1.0u
W=100.0u
nf=1
m=1
ad="'int((nf+1)/2) * W/nf * 0.18u'"
pd="'2*int((nf+1)/2) * (W/nf + 0.18u)'"
as="'int((nf+2)/2) * W/nf * 0.18u'"
ps="'2*int((nf+2)/2) * (W/nf + 0.18u)'"
nrd="'0.18u / W'" nrs="'0.18u / W'"
sa=0 sb=0 sd=0
model=pfet_06v0
spiceprefix=X
}
C {symbols/nfet_06v0.sym} -1180 250 0 0 {name=M47
L=1.0u
W=1.0u
nf=1
m=1
ad="'int((nf+1)/2) * W/nf * 0.18u'"
pd="'2*int((nf+1)/2) * (W/nf + 0.18u)'"
as="'int((nf+2)/2) * W/nf * 0.18u'"
ps="'2*int((nf+2)/2) * (W/nf + 0.18u)'"
nrd="'0.18u / W'" nrs="'0.18u / W'"
sa=0 sb=0 sd=0
model=nfet_06v0
spiceprefix=X
}
C {symbols/nfet_06v0.sym} -1280 270 0 1 {name=M48
L=1.0u
W=1.0u
nf=1
m=1
ad="'int((nf+1)/2) * W/nf * 0.18u'"
pd="'2*int((nf+1)/2) * (W/nf + 0.18u)'"
as="'int((nf+2)/2) * W/nf * 0.18u'"
ps="'2*int((nf+2)/2) * (W/nf + 0.18u)'"
nrd="'0.18u / W'" nrs="'0.18u / W'"
sa=0 sb=0 sd=0
model=nfet_06v0
spiceprefix=X
}
C {symbols/nfet_06v0.sym} -1280 210 0 1 {name=M49
L=1.0u
W=1.0u
nf=1
m=1
ad="'int((nf+1)/2) * W/nf * 0.18u'"
pd="'2*int((nf+1)/2) * (W/nf + 0.18u)'"
as="'int((nf+2)/2) * W/nf * 0.18u'"
ps="'2*int((nf+2)/2) * (W/nf + 0.18u)'"
nrd="'0.18u / W'" nrs="'0.18u / W'"
sa=0 sb=0 sd=0
model=nfet_06v0
spiceprefix=X
}
C {symbols/nfet_06v0.sym} -1280 120 0 1 {name=M50
L=1.0u
W=1.0u
nf=1
m=1
ad="'int((nf+1)/2) * W/nf * 0.18u'"
pd="'2*int((nf+1)/2) * (W/nf + 0.18u)'"
as="'int((nf+2)/2) * W/nf * 0.18u'"
ps="'2*int((nf+2)/2) * (W/nf + 0.18u)'"
nrd="'0.18u / W'" nrs="'0.18u / W'"
sa=0 sb=0 sd=0
model=nfet_06v0
spiceprefix=X
}
C {symbols/nfet_06v0.sym} -1280 50 0 1 {name=M51
L=1.0u
W=1.0u
nf=1
m=1
ad="'int((nf+1)/2) * W/nf * 0.18u'"
pd="'2*int((nf+1)/2) * (W/nf + 0.18u)'"
as="'int((nf+2)/2) * W/nf * 0.18u'"
ps="'2*int((nf+2)/2) * (W/nf + 0.18u)'"
nrd="'0.18u / W'" nrs="'0.18u / W'"
sa=0 sb=0 sd=0
model=nfet_06v0
spiceprefix=X
}
C {symbols/nfet_06v0.sym} -1280 -20 0 1 {name=M52
L=1.0u
W=1.0u
nf=1
m=1
ad="'int((nf+1)/2) * W/nf * 0.18u'"
pd="'2*int((nf+1)/2) * (W/nf + 0.18u)'"
as="'int((nf+2)/2) * W/nf * 0.18u'"
ps="'2*int((nf+2)/2) * (W/nf + 0.18u)'"
nrd="'0.18u / W'" nrs="'0.18u / W'"
sa=0 sb=0 sd=0
model=nfet_06v0
spiceprefix=X
}
C {symbols/nfet_06v0.sym} -1180 190 0 0 {name=M53
L=30.0u
W=1.0u
nf=1
m=1
ad="'int((nf+1)/2) * W/nf * 0.18u'"
pd="'2*int((nf+1)/2) * (W/nf + 0.18u)'"
as="'int((nf+2)/2) * W/nf * 0.18u'"
ps="'2*int((nf+2)/2) * (W/nf + 0.18u)'"
nrd="'0.18u / W'" nrs="'0.18u / W'"
sa=0 sb=0 sd=0
model=nfet_06v0
spiceprefix=X
}
C {symbols/nfet_06v0.sym} -1180 130 0 0 {name=M54
L=1.0u
W=1.0u
nf=1
m=1
ad="'int((nf+1)/2) * W/nf * 0.18u'"
pd="'2*int((nf+1)/2) * (W/nf + 0.18u)'"
as="'int((nf+2)/2) * W/nf * 0.18u'"
ps="'2*int((nf+2)/2) * (W/nf + 0.18u)'"
nrd="'0.18u / W'" nrs="'0.18u / W'"
sa=0 sb=0 sd=0
model=nfet_06v0
spiceprefix=X
}
C {symbols/nfet_06v0.sym} -1180 70 0 0 {name=M55
L=1.0u
W=1.0u
nf=1
m=1
ad="'int((nf+1)/2) * W/nf * 0.18u'"
pd="'2*int((nf+1)/2) * (W/nf + 0.18u)'"
as="'int((nf+2)/2) * W/nf * 0.18u'"
ps="'2*int((nf+2)/2) * (W/nf + 0.18u)'"
nrd="'0.18u / W'" nrs="'0.18u / W'"
sa=0 sb=0 sd=0
model=nfet_06v0
spiceprefix=X
}
C {symbols/nfet_06v0.sym} -1180 10 0 0 {name=M56
L=1.0u
W=1.0u
nf=1
m=1
ad="'int((nf+1)/2) * W/nf * 0.18u'"
pd="'2*int((nf+1)/2) * (W/nf + 0.18u)'"
as="'int((nf+2)/2) * W/nf * 0.18u'"
ps="'2*int((nf+2)/2) * (W/nf + 0.18u)'"
nrd="'0.18u / W'" nrs="'0.18u / W'"
sa=0 sb=0 sd=0
model=nfet_06v0
spiceprefix=X
}
C {symbols/nfet_06v0.sym} -1180 -50 0 0 {name=M57
L=1.0u
W=1.0u
nf=1
m=1
ad="'int((nf+1)/2) * W/nf * 0.18u'"
pd="'2*int((nf+1)/2) * (W/nf + 0.18u)'"
as="'int((nf+2)/2) * W/nf * 0.18u'"
ps="'2*int((nf+2)/2) * (W/nf + 0.18u)'"
nrd="'0.18u / W'" nrs="'0.18u / W'"
sa=0 sb=0 sd=0
model=nfet_06v0
spiceprefix=X
}
